VERSION 5.7 ;
NOWIREEXTENSIONATPIN ON ;
DIVIDERCHAR "/" ;
BUSBITCHARS "[]" ;
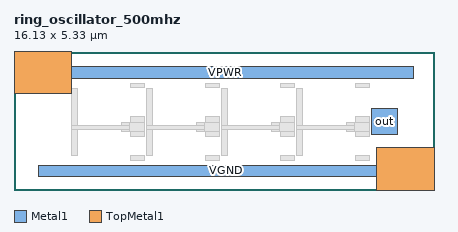
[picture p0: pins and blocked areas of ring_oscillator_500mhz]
MACRO ring_oscillator_500mhz
  CLASS BLOCK ;
  FOREIGN ring_oscillator_500mhz 0.000 0.000 ;
  ORIGIN 0.000 0.000 ;
  SIZE 16.130 BY 5.330 ;
  PIN out
    DIRECTION OUTPUT ;
    USE SIGNAL ;
    PORT
      LAYER Metal1 ;
        RECT 13.730 2.130 14.730 3.130 ;
    END
  END out
  PIN VPWR
    DIRECTION INOUT ;
    USE POWER ;
    PORT
      LAYER Metal1 ;
        RECT 0.930 4.290 15.330 4.730 ;
      LAYER TopMetal1 ;
        RECT 0.000 3.690 2.200 5.330 ;
    END
  END VPWR
  PIN VGND
    DIRECTION INOUT ;
    USE GROUND ;
    PORT
      LAYER Metal1 ;
        RECT 0.930 0.510 15.330 0.950 ;
      LAYER TopMetal1 ;
        RECT 13.930 0.000 16.130 1.640 ;
    END
  END VGND
  OBS
      LAYER GatPoly ;
        RECT 4.460 3.925 5.015 4.105 ;
        RECT 7.340 3.925 7.895 4.105 ;
        RECT 10.220 3.925 10.775 4.105 ;
        RECT 13.100 3.925 13.655 4.105 ;
        RECT 4.460 2.580 5.015 2.805 ;
        RECT 7.340 2.580 7.895 2.805 ;
        RECT 10.220 2.580 10.775 2.805 ;
        RECT 13.100 2.580 13.655 2.805 ;
        RECT 4.120 2.250 5.015 2.580 ;
        RECT 7.000 2.250 7.895 2.580 ;
        RECT 9.880 2.250 10.775 2.580 ;
        RECT 12.760 2.250 13.655 2.580 ;
        RECT 4.460 2.060 5.015 2.250 ;
        RECT 7.340 2.060 7.895 2.250 ;
        RECT 10.220 2.060 10.775 2.250 ;
        RECT 13.100 2.060 13.655 2.250 ;
        RECT 4.460 1.140 5.015 1.320 ;
        RECT 7.340 1.140 7.895 1.320 ;
        RECT 10.220 1.140 10.775 1.320 ;
        RECT 13.100 1.140 13.655 1.320 ;
      LAYER Metal1 ;
        RECT 2.210 2.495 2.440 3.905 ;
        RECT 4.120 2.495 4.435 2.580 ;
        RECT 2.210 2.335 4.435 2.495 ;
        RECT 2.210 1.340 2.440 2.335 ;
        RECT 4.120 2.250 4.435 2.335 ;
        RECT 5.090 2.495 5.320 3.905 ;
        RECT 7.000 2.495 7.315 2.580 ;
        RECT 5.090 2.335 7.315 2.495 ;
        RECT 5.090 1.340 5.320 2.335 ;
        RECT 7.000 2.250 7.315 2.335 ;
        RECT 7.970 2.495 8.200 3.905 ;
        RECT 9.880 2.495 10.195 2.580 ;
        RECT 7.970 2.335 10.195 2.495 ;
        RECT 7.970 1.340 8.200 2.335 ;
        RECT 9.880 2.250 10.195 2.335 ;
        RECT 10.850 2.495 11.080 3.905 ;
        RECT 12.760 2.495 13.075 2.580 ;
        RECT 10.850 2.335 13.075 2.495 ;
        RECT 10.850 1.340 11.080 2.335 ;
        RECT 12.760 2.250 13.075 2.335 ;
  END
END ring_oscillator_500mhz
END LIBRARY
